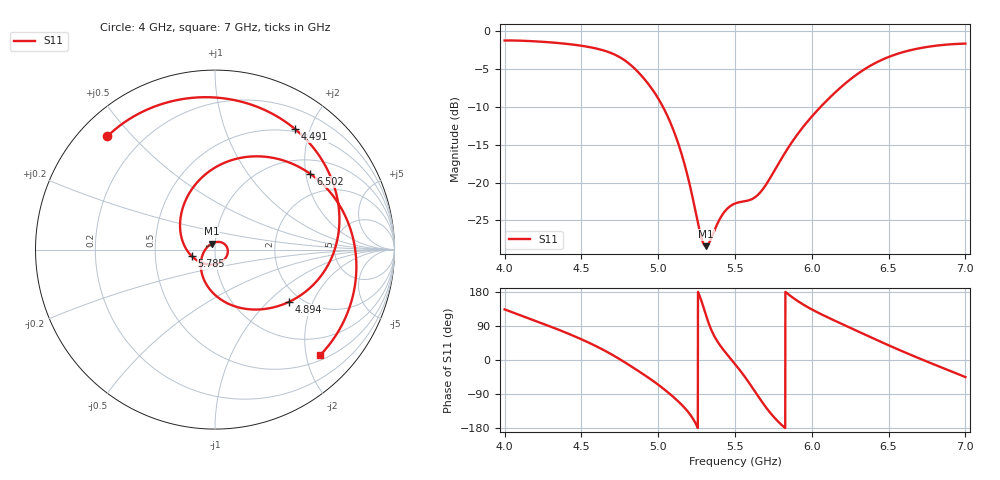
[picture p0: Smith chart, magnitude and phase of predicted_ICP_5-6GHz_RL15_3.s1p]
! ICP-predicted S11, target 5.000-6.000 GHz at -15 dB. Complex ensemble mean (passive and causal);
! its |S11| can differ slightly from the dB-domain mean reported in designs.csv.
!  Air_gap = 2.8mm
!  W_Patch = 13.69mm
!  L_Patch = 16.68mm
!  Sx = 0.75mm
!  Sy = 4.41mm
!  W_Patch1 = 9.69mm
!  WS = 1.18mm
!  Curve_Amp1 = 2.41mm
!  Extra = 7.12mm
# GHz S MA R 50
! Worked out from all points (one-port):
!   3001 points, 4 GHz to 7 GHz, reference 50 ohm
!   lowest |S11| = -28.4 dB at 5.311 GHz (marker M1), VSWR 1.08, Z = 48.1 + j3.22 ohm
!   |S11| at or under -10 dB: 5.031 GHz to 6.057 GHz (1.025 GHz wide, 18.5 % of centre)
!   S11 on the Smith chart (normalised r, x): 4 GHz: 0.08, +0.43; 4.491 GHz: 0.46, +1.78; 4.894 GHz: 1.74, -1.36; 5.785 GHz: 0.77, -0.06; 6.502 GHz: 1.36, +2.12; 7 GHz: 0.60, -2.28
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4  0.8703 133.6
4.195  0.8596 104.3
4.286  0.8478 90.3
4.375  0.8327 76.1
4.491  0.806 56.3
4.636  0.7523 28.2
4.75  0.6746 2.1
4.828  0.5908 -17.8
4.894  0.5053 -35.2
5.001  0.3587 -65.5
5.125  0.1884 -107.2
5.192  0.1101 -135.7
5.278  0.04444 159.9
5.311  0.03799 118.3
5.422  0.06224 28.2
5.5  0.07271 -10.7
5.647  0.08258 -93.4
5.785  0.1344 -164.1
5.875  0.1879 164.9
6.069  0.3259 119.3
6.25  0.481 85.0
6.378  0.5903 61.1
6.502  0.6784 38.5
6.625  0.7434 16.9
6.716  0.7783 1.5
6.807  0.8036 -13.5
6.897  0.8204 -28.2
7  0.8302 -45.0
